VERSION 5.7 ;
  NOWIREEXTENSIONATPIN ON ;
  DIVIDERCHAR "/" ;
  BUSBITCHARS "[]" ;
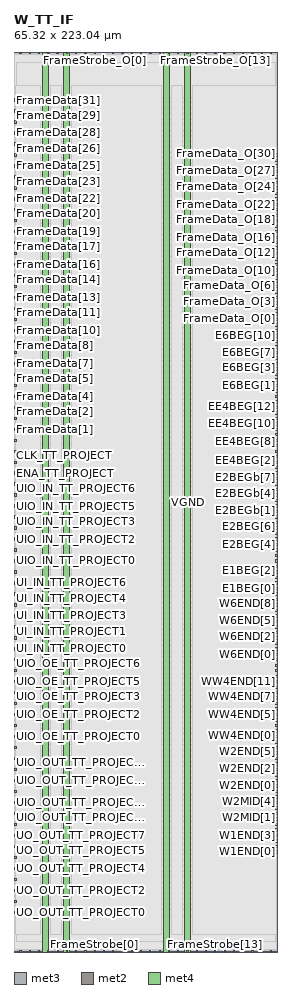
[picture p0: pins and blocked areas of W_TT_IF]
MACRO W_TT_IF
  CLASS BLOCK ;
  FOREIGN W_TT_IF ;
  ORIGIN 0.000 0.000 ;
  SIZE 65.320 BY 223.040 ;
  PIN CLK_TT_PROJECT
    DIRECTION OUTPUT ;
    USE SIGNAL ;
    ANTENNADIFFAREA 0.702900 ;
    PORT
      LAYER met3 ;
        RECT 0.000 121.080 0.600 121.680 ;
    END
  END CLK_TT_PROJECT
  PIN E1BEG[0]
    DIRECTION OUTPUT ;
    USE SIGNAL ;
    ANTENNADIFFAREA 0.702900 ;
    PORT
      LAYER met3 ;
        RECT 64.720 89.800 65.320 90.400 ;
    END
  END E1BEG[0]
  PIN E1BEG[1]
    DIRECTION OUTPUT ;
    USE SIGNAL ;
    ANTENNADIFFAREA 0.702900 ;
    PORT
      LAYER met3 ;
        RECT 64.720 91.160 65.320 91.760 ;
    END
  END E1BEG[1]
  PIN E1BEG[2]
    DIRECTION OUTPUT ;
    USE SIGNAL ;
    ANTENNADIFFAREA 0.702900 ;
    PORT
      LAYER met3 ;
        RECT 64.720 92.520 65.320 93.120 ;
    END
  END E1BEG[2]
  PIN E1BEG[3]
    DIRECTION OUTPUT ;
    USE SIGNAL ;
    ANTENNADIFFAREA 0.702900 ;
    PORT
      LAYER met3 ;
        RECT 64.720 93.880 65.320 94.480 ;
    END
  END E1BEG[3]
  PIN E2BEG[0]
    DIRECTION OUTPUT ;
    USE SIGNAL ;
    ANTENNADIFFAREA 0.702900 ;
    PORT
      LAYER met3 ;
        RECT 64.720 95.240 65.320 95.840 ;
    END
  END E2BEG[0]
  PIN E2BEG[1]
    DIRECTION OUTPUT ;
    USE SIGNAL ;
    ANTENNADIFFAREA 0.702900 ;
    PORT
      LAYER met3 ;
        RECT 64.720 96.600 65.320 97.200 ;
    END
  END E2BEG[1]
  PIN E2BEG[2]
    DIRECTION OUTPUT ;
    USE SIGNAL ;
    ANTENNADIFFAREA 0.702900 ;
    PORT
      LAYER met3 ;
        RECT 64.720 97.960 65.320 98.560 ;
    END
  END E2BEG[2]
  PIN E2BEG[3]
    DIRECTION OUTPUT ;
    USE SIGNAL ;
    ANTENNADIFFAREA 0.702900 ;
    PORT
      LAYER met3 ;
        RECT 64.720 99.320 65.320 99.920 ;
    END
  END E2BEG[3]
  PIN E2BEG[4]
    DIRECTION OUTPUT ;
    USE SIGNAL ;
    ANTENNADIFFAREA 0.702900 ;
    PORT
      LAYER met3 ;
        RECT 64.720 100.680 65.320 101.280 ;
    END
  END E2BEG[4]
  PIN E2BEG[5]
    DIRECTION OUTPUT ;
    USE SIGNAL ;
    ANTENNADIFFAREA 0.702900 ;
    PORT
      LAYER met3 ;
        RECT 64.720 102.040 65.320 102.640 ;
    END
  END E2BEG[5]
  PIN E2BEG[6]
    DIRECTION OUTPUT ;
    USE SIGNAL ;
    ANTENNADIFFAREA 0.702900 ;
    PORT
      LAYER met3 ;
        RECT 64.720 103.400 65.320 104.000 ;
    END
  END E2BEG[6]
  PIN E2BEG[7]
    DIRECTION OUTPUT ;
    USE SIGNAL ;
    ANTENNADIFFAREA 0.702900 ;
    PORT
      LAYER met3 ;
        RECT 64.720 104.760 65.320 105.360 ;
    END
  END E2BEG[7]
  PIN E2BEGb[0]
    DIRECTION OUTPUT ;
    USE SIGNAL ;
    ANTENNADIFFAREA 0.702900 ;
    PORT
      LAYER met3 ;
        RECT 64.720 106.120 65.320 106.720 ;
    END
  END E2BEGb[0]
  PIN E2BEGb[1]
    DIRECTION OUTPUT ;
    USE SIGNAL ;
    ANTENNADIFFAREA 0.702900 ;
    PORT
      LAYER met3 ;
        RECT 64.720 107.480 65.320 108.080 ;
    END
  END E2BEGb[1]
  PIN E2BEGb[2]
    DIRECTION OUTPUT ;
    USE SIGNAL ;
    ANTENNADIFFAREA 0.702900 ;
    PORT
      LAYER met3 ;
        RECT 64.720 108.840 65.320 109.440 ;
    END
  END E2BEGb[2]
  PIN E2BEGb[3]
    DIRECTION OUTPUT ;
    USE SIGNAL ;
    ANTENNADIFFAREA 0.702900 ;
    PORT
      LAYER met3 ;
        RECT 64.720 110.200 65.320 110.800 ;
    END
  END E2BEGb[3]
  PIN E2BEGb[4]
    DIRECTION OUTPUT ;
    USE SIGNAL ;
    ANTENNADIFFAREA 0.702900 ;
    PORT
      LAYER met3 ;
        RECT 64.720 111.560 65.320 112.160 ;
    END
  END E2BEGb[4]
  PIN E2BEGb[5]
    DIRECTION OUTPUT ;
    USE SIGNAL ;
    ANTENNADIFFAREA 0.702900 ;
    PORT
      LAYER met3 ;
        RECT 64.720 112.920 65.320 113.520 ;
    END
  END E2BEGb[5]
  PIN E2BEGb[6]
    DIRECTION OUTPUT ;
    USE SIGNAL ;
    ANTENNADIFFAREA 0.702900 ;
    PORT
      LAYER met3 ;
        RECT 64.720 114.280 65.320 114.880 ;
    END
  END E2BEGb[6]
  PIN E2BEGb[7]
    DIRECTION OUTPUT ;
    USE SIGNAL ;
    ANTENNADIFFAREA 0.702900 ;
    PORT
      LAYER met3 ;
        RECT 64.720 115.640 65.320 116.240 ;
    END
  END E2BEGb[7]
  PIN E6BEG[0]
    DIRECTION OUTPUT ;
    USE SIGNAL ;
    ANTENNADIFFAREA 0.702900 ;
    PORT
      LAYER met3 ;
        RECT 64.720 138.760 65.320 139.360 ;
    END
  END E6BEG[0]
  PIN E6BEG[10]
    DIRECTION OUTPUT ;
    USE SIGNAL ;
    ANTENNADIFFAREA 0.702900 ;
    PORT
      LAYER met3 ;
        RECT 64.720 152.360 65.320 152.960 ;
    END
  END E6BEG[10]
  PIN E6BEG[11]
    DIRECTION OUTPUT ;
    USE SIGNAL ;
    ANTENNADIFFAREA 0.702900 ;
    PORT
      LAYER met3 ;
        RECT 64.720 153.720 65.320 154.320 ;
    END
  END E6BEG[11]
  PIN E6BEG[1]
    DIRECTION OUTPUT ;
    USE SIGNAL ;
    ANTENNADIFFAREA 0.702900 ;
    PORT
      LAYER met3 ;
        RECT 64.720 140.120 65.320 140.720 ;
    END
  END E6BEG[1]
  PIN E6BEG[2]
    DIRECTION OUTPUT ;
    USE SIGNAL ;
    ANTENNADIFFAREA 0.702900 ;
    PORT
      LAYER met3 ;
        RECT 64.720 141.480 65.320 142.080 ;
    END
  END E6BEG[2]
  PIN E6BEG[3]
    DIRECTION OUTPUT ;
    USE SIGNAL ;
    ANTENNADIFFAREA 0.702900 ;
    PORT
      LAYER met3 ;
        RECT 64.720 142.840 65.320 143.440 ;
    END
  END E6BEG[3]
  PIN E6BEG[4]
    DIRECTION OUTPUT ;
    USE SIGNAL ;
    ANTENNADIFFAREA 0.702900 ;
    PORT
      LAYER met3 ;
        RECT 64.720 144.200 65.320 144.800 ;
    END
  END E6BEG[4]
  PIN E6BEG[5]
    DIRECTION OUTPUT ;
    USE SIGNAL ;
    ANTENNADIFFAREA 0.702900 ;
    PORT
      LAYER met3 ;
        RECT 64.720 145.560 65.320 146.160 ;
    END
  END E6BEG[5]
  PIN E6BEG[6]
    DIRECTION OUTPUT ;
    USE SIGNAL ;
    ANTENNADIFFAREA 0.702900 ;
    PORT
      LAYER met3 ;
        RECT 64.720 146.920 65.320 147.520 ;
    END
  END E6BEG[6]
  PIN E6BEG[7]
    DIRECTION OUTPUT ;
    USE SIGNAL ;
    ANTENNADIFFAREA 0.702900 ;
    PORT
      LAYER met3 ;
        RECT 64.720 148.280 65.320 148.880 ;
    END
  END E6BEG[7]
  PIN E6BEG[8]
    DIRECTION OUTPUT ;
    USE SIGNAL ;
    ANTENNADIFFAREA 0.702900 ;
    PORT
      LAYER met3 ;
        RECT 64.720 149.640 65.320 150.240 ;
    END
  END E6BEG[8]
  PIN E6BEG[9]
    DIRECTION OUTPUT ;
    USE SIGNAL ;
    ANTENNADIFFAREA 0.702900 ;
    PORT
      LAYER met3 ;
        RECT 64.720 151.000 65.320 151.600 ;
    END
  END E6BEG[9]
  PIN EE4BEG[0]
    DIRECTION OUTPUT ;
    USE SIGNAL ;
    ANTENNADIFFAREA 0.702900 ;
    PORT
      LAYER met3 ;
        RECT 64.720 117.000 65.320 117.600 ;
    END
  END EE4BEG[0]
  PIN EE4BEG[10]
    DIRECTION OUTPUT ;
    USE SIGNAL ;
    ANTENNADIFFAREA 0.702900 ;
    PORT
      LAYER met3 ;
        RECT 64.720 130.600 65.320 131.200 ;
    END
  END EE4BEG[10]
  PIN EE4BEG[11]
    DIRECTION OUTPUT ;
    USE SIGNAL ;
    ANTENNADIFFAREA 0.702900 ;
    PORT
      LAYER met3 ;
        RECT 64.720 131.960 65.320 132.560 ;
    END
  END EE4BEG[11]
  PIN EE4BEG[12]
    DIRECTION OUTPUT ;
    USE SIGNAL ;
    ANTENNADIFFAREA 0.702900 ;
    PORT
      LAYER met3 ;
        RECT 64.720 133.320 65.320 133.920 ;
    END
  END EE4BEG[12]
  PIN EE4BEG[13]
    DIRECTION OUTPUT ;
    USE SIGNAL ;
    ANTENNADIFFAREA 0.702900 ;
    PORT
      LAYER met3 ;
        RECT 64.720 134.680 65.320 135.280 ;
    END
  END EE4BEG[13]
  PIN EE4BEG[14]
    DIRECTION OUTPUT ;
    USE SIGNAL ;
    ANTENNADIFFAREA 0.702900 ;
    PORT
      LAYER met3 ;
        RECT 64.720 136.040 65.320 136.640 ;
    END
  END EE4BEG[14]
  PIN EE4BEG[15]
    DIRECTION OUTPUT ;
    USE SIGNAL ;
    ANTENNADIFFAREA 0.702900 ;
    PORT
      LAYER met3 ;
        RECT 64.720 137.400 65.320 138.000 ;
    END
  END EE4BEG[15]
  PIN EE4BEG[1]
    DIRECTION OUTPUT ;
    USE SIGNAL ;
    ANTENNADIFFAREA 0.702900 ;
    PORT
      LAYER met3 ;
        RECT 64.720 118.360 65.320 118.960 ;
    END
  END EE4BEG[1]
  PIN EE4BEG[2]
    DIRECTION OUTPUT ;
    USE SIGNAL ;
    ANTENNADIFFAREA 0.702900 ;
    PORT
      LAYER met3 ;
        RECT 64.720 119.720 65.320 120.320 ;
    END
  END EE4BEG[2]
  PIN EE4BEG[3]
    DIRECTION OUTPUT ;
    USE SIGNAL ;
    ANTENNADIFFAREA 0.702900 ;
    PORT
      LAYER met3 ;
        RECT 64.720 121.080 65.320 121.680 ;
    END
  END EE4BEG[3]
  PIN EE4BEG[4]
    DIRECTION OUTPUT ;
    USE SIGNAL ;
    ANTENNADIFFAREA 0.702900 ;
    PORT
      LAYER met3 ;
        RECT 64.720 122.440 65.320 123.040 ;
    END
  END EE4BEG[4]
  PIN EE4BEG[5]
    DIRECTION OUTPUT ;
    USE SIGNAL ;
    ANTENNADIFFAREA 0.702900 ;
    PORT
      LAYER met3 ;
        RECT 64.720 123.800 65.320 124.400 ;
    END
  END EE4BEG[5]
  PIN EE4BEG[6]
    DIRECTION OUTPUT ;
    USE SIGNAL ;
    ANTENNADIFFAREA 0.702900 ;
    PORT
      LAYER met3 ;
        RECT 64.720 125.160 65.320 125.760 ;
    END
  END EE4BEG[6]
  PIN EE4BEG[7]
    DIRECTION OUTPUT ;
    USE SIGNAL ;
    ANTENNADIFFAREA 0.702900 ;
    PORT
      LAYER met3 ;
        RECT 64.720 126.520 65.320 127.120 ;
    END
  END EE4BEG[7]
  PIN EE4BEG[8]
    DIRECTION OUTPUT ;
    USE SIGNAL ;
    ANTENNADIFFAREA 0.702900 ;
    PORT
      LAYER met3 ;
        RECT 64.720 127.880 65.320 128.480 ;
    END
  END EE4BEG[8]
  PIN EE4BEG[9]
    DIRECTION OUTPUT ;
    USE SIGNAL ;
    ANTENNADIFFAREA 0.702900 ;
    PORT
      LAYER met3 ;
        RECT 64.720 129.240 65.320 129.840 ;
    END
  END EE4BEG[9]
  PIN ENA_TT_PROJECT
    DIRECTION OUTPUT ;
    USE SIGNAL ;
    ANTENNADIFFAREA 0.702900 ;
    PORT
      LAYER met3 ;
        RECT 0.000 118.360 0.600 118.960 ;
    END
  END ENA_TT_PROJECT
  PIN FrameData[0]
    DIRECTION INPUT ;
    USE SIGNAL ;
    ANTENNAGATEAREA 0.954000 ;
    PORT
      LAYER met3 ;
        RECT 0.000 126.520 0.600 127.120 ;
    END
  END FrameData[0]
  PIN FrameData[10]
    DIRECTION INPUT ;
    USE SIGNAL ;
    ANTENNAGATEAREA 1.823400 ;
    ANTENNADIFFAREA 0.869400 ;
    PORT
      LAYER met3 ;
        RECT 0.000 153.720 0.600 154.320 ;
    END
  END FrameData[10]
  PIN FrameData[11]
    DIRECTION INPUT ;
    USE SIGNAL ;
    ANTENNAGATEAREA 0.954000 ;
    PORT
      LAYER met3 ;
        RECT 0.000 156.440 0.600 157.040 ;
    END
  END FrameData[11]
  PIN FrameData[12]
    DIRECTION INPUT ;
    USE SIGNAL ;
    ANTENNAGATEAREA 0.954000 ;
    PORT
      LAYER met3 ;
        RECT 0.000 159.160 0.600 159.760 ;
    END
  END FrameData[12]
  PIN FrameData[13]
    DIRECTION INPUT ;
    USE SIGNAL ;
    ANTENNAGATEAREA 1.823400 ;
    ANTENNADIFFAREA 0.869400 ;
    PORT
      LAYER met3 ;
        RECT 0.000 161.880 0.600 162.480 ;
    END
  END FrameData[13]
  PIN FrameData[14]
    DIRECTION INPUT ;
    USE SIGNAL ;
    ANTENNAGATEAREA 0.954000 ;
    PORT
      LAYER met3 ;
        RECT 0.000 164.600 0.600 165.200 ;
    END
  END FrameData[14]
  PIN FrameData[15]
    DIRECTION INPUT ;
    USE SIGNAL ;
    ANTENNAGATEAREA 0.954000 ;
    PORT
      LAYER met3 ;
        RECT 0.000 167.320 0.600 167.920 ;
    END
  END FrameData[15]
  PIN FrameData[16]
    DIRECTION INPUT ;
    USE SIGNAL ;
    ANTENNAGATEAREA 0.954000 ;
    PORT
      LAYER met3 ;
        RECT 0.000 170.040 0.600 170.640 ;
    END
  END FrameData[16]
  PIN FrameData[17]
    DIRECTION INPUT ;
    USE SIGNAL ;
    ANTENNAGATEAREA 0.954000 ;
    PORT
      LAYER met3 ;
        RECT 0.000 172.760 0.600 173.360 ;
    END
  END FrameData[17]
  PIN FrameData[18]
    DIRECTION INPUT ;
    USE SIGNAL ;
    ANTENNAGATEAREA 0.954000 ;
    PORT
      LAYER met3 ;
        RECT 0.000 175.480 0.600 176.080 ;
    END
  END FrameData[18]
  PIN FrameData[19]
    DIRECTION INPUT ;
    USE SIGNAL ;
    ANTENNAGATEAREA 0.954000 ;
    PORT
      LAYER met3 ;
        RECT 0.000 178.200 0.600 178.800 ;
    END
  END FrameData[19]
  PIN FrameData[1]
    DIRECTION INPUT ;
    USE SIGNAL ;
    ANTENNAGATEAREA 0.954000 ;
    PORT
      LAYER met3 ;
        RECT 0.000 129.240 0.600 129.840 ;
    END
  END FrameData[1]
  PIN FrameData[20]
    DIRECTION INPUT ;
    USE SIGNAL ;
    ANTENNAGATEAREA 1.388700 ;
    ANTENNADIFFAREA 0.434700 ;
    PORT
      LAYER met3 ;
        RECT 0.000 180.920 0.600 181.520 ;
    END
  END FrameData[20]
  PIN FrameData[21]
    DIRECTION INPUT ;
    USE SIGNAL ;
    ANTENNAGATEAREA 0.954000 ;
    PORT
      LAYER met3 ;
        RECT 0.000 183.640 0.600 184.240 ;
    END
  END FrameData[21]
  PIN FrameData[22]
    DIRECTION INPUT ;
    USE SIGNAL ;
    ANTENNAGATEAREA 1.388700 ;
    ANTENNADIFFAREA 0.434700 ;
    PORT
      LAYER met3 ;
        RECT 0.000 186.360 0.600 186.960 ;
    END
  END FrameData[22]
  PIN FrameData[23]
    DIRECTION INPUT ;
    USE SIGNAL ;
    ANTENNAGATEAREA 0.954000 ;
    PORT
      LAYER met3 ;
        RECT 0.000 189.080 0.600 189.680 ;
    END
  END FrameData[23]
  PIN FrameData[24]
    DIRECTION INPUT ;
    USE SIGNAL ;
    ANTENNAGATEAREA 0.954000 ;
    PORT
      LAYER met3 ;
        RECT 0.000 191.800 0.600 192.400 ;
    END
  END FrameData[24]
  PIN FrameData[25]
    DIRECTION INPUT ;
    USE SIGNAL ;
    ANTENNAGATEAREA 0.954000 ;
    PORT
      LAYER met3 ;
        RECT 0.000 194.520 0.600 195.120 ;
    END
  END FrameData[25]
  PIN FrameData[26]
    DIRECTION INPUT ;
    USE SIGNAL ;
    ANTENNAGATEAREA 0.954000 ;
    PORT
      LAYER met3 ;
        RECT 0.000 197.240 0.600 197.840 ;
    END
  END FrameData[26]
  PIN FrameData[27]
    DIRECTION INPUT ;
    USE SIGNAL ;
    ANTENNAGATEAREA 1.113000 ;
    PORT
      LAYER met3 ;
        RECT 0.000 199.960 0.600 200.560 ;
    END
  END FrameData[27]
  PIN FrameData[28]
    DIRECTION INPUT ;
    USE SIGNAL ;
    ANTENNAGATEAREA 1.113000 ;
    PORT
      LAYER met3 ;
        RECT 0.000 202.680 0.600 203.280 ;
    END
  END FrameData[28]
  PIN FrameData[29]
    DIRECTION INPUT ;
    USE SIGNAL ;
    ANTENNAGATEAREA 1.113000 ;
    PORT
      LAYER met3 ;
        RECT 0.000 205.400 0.600 206.000 ;
    END
  END FrameData[29]
  PIN FrameData[2]
    DIRECTION INPUT ;
    USE SIGNAL ;
    ANTENNAGATEAREA 0.954000 ;
    PORT
      LAYER met3 ;
        RECT 0.000 131.960 0.600 132.560 ;
    END
  END FrameData[2]
  PIN FrameData[30]
    DIRECTION INPUT ;
    USE SIGNAL ;
    ANTENNAGATEAREA 1.113000 ;
    PORT
      LAYER met3 ;
        RECT 0.000 208.120 0.600 208.720 ;
    END
  END FrameData[30]
  PIN FrameData[31]
    DIRECTION INPUT ;
    USE SIGNAL ;
    ANTENNAGATEAREA 1.113000 ;
    PORT
      LAYER met3 ;
        RECT 0.000 210.840 0.600 211.440 ;
    END
  END FrameData[31]
  PIN FrameData[3]
    DIRECTION INPUT ;
    USE SIGNAL ;
    ANTENNAGATEAREA 1.388700 ;
    ANTENNADIFFAREA 0.434700 ;
    PORT
      LAYER met3 ;
        RECT 0.000 134.680 0.600 135.280 ;
    END
  END FrameData[3]
  PIN FrameData[4]
    DIRECTION INPUT ;
    USE SIGNAL ;
    ANTENNAGATEAREA 1.388700 ;
    ANTENNADIFFAREA 0.434700 ;
    PORT
      LAYER met3 ;
        RECT 0.000 137.400 0.600 138.000 ;
    END
  END FrameData[4]
  PIN FrameData[5]
    DIRECTION INPUT ;
    USE SIGNAL ;
    ANTENNAGATEAREA 0.954000 ;
    PORT
      LAYER met3 ;
        RECT 0.000 140.120 0.600 140.720 ;
    END
  END FrameData[5]
  PIN FrameData[6]
    DIRECTION INPUT ;
    USE SIGNAL ;
    ANTENNAGATEAREA 0.954000 ;
    PORT
      LAYER met3 ;
        RECT 0.000 142.840 0.600 143.440 ;
    END
  END FrameData[6]
  PIN FrameData[7]
    DIRECTION INPUT ;
    USE SIGNAL ;
    ANTENNAGATEAREA 0.954000 ;
    PORT
      LAYER met3 ;
        RECT 0.000 145.560 0.600 146.160 ;
    END
  END FrameData[7]
  PIN FrameData[8]
    DIRECTION INPUT ;
    USE SIGNAL ;
    ANTENNAGATEAREA 1.388700 ;
    ANTENNADIFFAREA 0.434700 ;
    PORT
      LAYER met3 ;
        RECT 0.000 148.280 0.600 148.880 ;
    END
  END FrameData[8]
  PIN FrameData[9]
    DIRECTION INPUT ;
    USE SIGNAL ;
    ANTENNAGATEAREA 0.954000 ;
    PORT
      LAYER met3 ;
        RECT 0.000 151.000 0.600 151.600 ;
    END
  END FrameData[9]
  PIN FrameData_O[0]
    DIRECTION OUTPUT ;
    USE SIGNAL ;
    ANTENNADIFFAREA 0.702900 ;
    PORT
      LAYER met3 ;
        RECT 64.720 155.080 65.320 155.680 ;
    END
  END FrameData_O[0]
  PIN FrameData_O[10]
    DIRECTION OUTPUT ;
    USE SIGNAL ;
    ANTENNADIFFAREA 0.702900 ;
    PORT
      LAYER met3 ;
        RECT 64.720 168.680 65.320 169.280 ;
    END
  END FrameData_O[10]
  PIN FrameData_O[11]
    DIRECTION OUTPUT ;
    USE SIGNAL ;
    ANTENNADIFFAREA 0.702900 ;
    PORT
      LAYER met3 ;
        RECT 64.720 170.040 65.320 170.640 ;
    END
  END FrameData_O[11]
  PIN FrameData_O[12]
    DIRECTION OUTPUT ;
    USE SIGNAL ;
    ANTENNADIFFAREA 0.702900 ;
    PORT
      LAYER met3 ;
        RECT 64.720 171.400 65.320 172.000 ;
    END
  END FrameData_O[12]
  PIN FrameData_O[13]
    DIRECTION OUTPUT ;
    USE SIGNAL ;
    ANTENNADIFFAREA 0.702900 ;
    PORT
      LAYER met3 ;
        RECT 64.720 172.760 65.320 173.360 ;
    END
  END FrameData_O[13]
  PIN FrameData_O[14]
    DIRECTION OUTPUT ;
    USE SIGNAL ;
    ANTENNADIFFAREA 0.702900 ;
    PORT
      LAYER met3 ;
        RECT 64.720 174.120 65.320 174.720 ;
    END
  END FrameData_O[14]
  PIN FrameData_O[15]
    DIRECTION OUTPUT ;
    USE SIGNAL ;
    ANTENNADIFFAREA 0.702900 ;
    PORT
      LAYER met3 ;
        RECT 64.720 175.480 65.320 176.080 ;
    END
  END FrameData_O[15]
  PIN FrameData_O[16]
    DIRECTION OUTPUT ;
    USE SIGNAL ;
    ANTENNADIFFAREA 0.702900 ;
    PORT
      LAYER met3 ;
        RECT 64.720 176.840 65.320 177.440 ;
    END
  END FrameData_O[16]
  PIN FrameData_O[17]
    DIRECTION OUTPUT ;
    USE SIGNAL ;
    ANTENNADIFFAREA 0.702900 ;
    PORT
      LAYER met3 ;
        RECT 64.720 178.200 65.320 178.800 ;
    END
  END FrameData_O[17]
  PIN FrameData_O[18]
    DIRECTION OUTPUT ;
    USE SIGNAL ;
    ANTENNADIFFAREA 0.702900 ;
    PORT
      LAYER met3 ;
        RECT 64.720 179.560 65.320 180.160 ;
    END
  END FrameData_O[18]
  PIN FrameData_O[19]
    DIRECTION OUTPUT ;
    USE SIGNAL ;
    ANTENNADIFFAREA 0.702900 ;
    PORT
      LAYER met3 ;
        RECT 64.720 180.920 65.320 181.520 ;
    END
  END FrameData_O[19]
  PIN FrameData_O[1]
    DIRECTION OUTPUT ;
    USE SIGNAL ;
    ANTENNADIFFAREA 0.702900 ;
    PORT
      LAYER met3 ;
        RECT 64.720 156.440 65.320 157.040 ;
    END
  END FrameData_O[1]
  PIN FrameData_O[20]
    DIRECTION OUTPUT ;
    USE SIGNAL ;
    ANTENNADIFFAREA 0.702900 ;
    PORT
      LAYER met3 ;
        RECT 64.720 182.280 65.320 182.880 ;
    END
  END FrameData_O[20]
  PIN FrameData_O[21]
    DIRECTION OUTPUT ;
    USE SIGNAL ;
    ANTENNADIFFAREA 0.702900 ;
    PORT
      LAYER met3 ;
        RECT 64.720 183.640 65.320 184.240 ;
    END
  END FrameData_O[21]
  PIN FrameData_O[22]
    DIRECTION OUTPUT ;
    USE SIGNAL ;
    ANTENNADIFFAREA 0.702900 ;
    PORT
      LAYER met3 ;
        RECT 64.720 185.000 65.320 185.600 ;
    END
  END FrameData_O[22]
  PIN FrameData_O[23]
    DIRECTION OUTPUT ;
    USE SIGNAL ;
    ANTENNADIFFAREA 0.702900 ;
    PORT
      LAYER met3 ;
        RECT 64.720 186.360 65.320 186.960 ;
    END
  END FrameData_O[23]
  PIN FrameData_O[24]
    DIRECTION OUTPUT ;
    USE SIGNAL ;
    ANTENNADIFFAREA 0.702900 ;
    PORT
      LAYER met3 ;
        RECT 64.720 187.720 65.320 188.320 ;
    END
  END FrameData_O[24]
  PIN FrameData_O[25]
    DIRECTION OUTPUT ;
    USE SIGNAL ;
    ANTENNADIFFAREA 0.702900 ;
    PORT
      LAYER met3 ;
        RECT 64.720 189.080 65.320 189.680 ;
    END
  END FrameData_O[25]
  PIN FrameData_O[26]
    DIRECTION OUTPUT ;
    USE SIGNAL ;
    ANTENNADIFFAREA 0.702900 ;
    PORT
      LAYER met3 ;
        RECT 64.720 190.440 65.320 191.040 ;
    END
  END FrameData_O[26]
  PIN FrameData_O[27]
    DIRECTION OUTPUT ;
    USE SIGNAL ;
    ANTENNADIFFAREA 0.702900 ;
    PORT
      LAYER met3 ;
        RECT 64.720 191.800 65.320 192.400 ;
    END
  END FrameData_O[27]
  PIN FrameData_O[28]
    DIRECTION OUTPUT ;
    USE SIGNAL ;
    ANTENNADIFFAREA 0.702900 ;
    PORT
      LAYER met3 ;
        RECT 64.720 193.160 65.320 193.760 ;
    END
  END FrameData_O[28]
  PIN FrameData_O[29]
    DIRECTION OUTPUT ;
    USE SIGNAL ;
    ANTENNADIFFAREA 0.702900 ;
    PORT
      LAYER met3 ;
        RECT 64.720 194.520 65.320 195.120 ;
    END
  END FrameData_O[29]
  PIN FrameData_O[2]
    DIRECTION OUTPUT ;
    USE SIGNAL ;
    ANTENNADIFFAREA 0.702900 ;
    PORT
      LAYER met3 ;
        RECT 64.720 157.800 65.320 158.400 ;
    END
  END FrameData_O[2]
  PIN FrameData_O[30]
    DIRECTION OUTPUT ;
    USE SIGNAL ;
    ANTENNADIFFAREA 0.702900 ;
    PORT
      LAYER met3 ;
        RECT 64.720 195.880 65.320 196.480 ;
    END
  END FrameData_O[30]
  PIN FrameData_O[31]
    DIRECTION OUTPUT ;
    USE SIGNAL ;
    ANTENNADIFFAREA 0.702900 ;
    PORT
      LAYER met3 ;
        RECT 64.720 197.240 65.320 197.840 ;
    END
  END FrameData_O[31]
  PIN FrameData_O[3]
    DIRECTION OUTPUT ;
    USE SIGNAL ;
    ANTENNADIFFAREA 0.702900 ;
    PORT
      LAYER met3 ;
        RECT 64.720 159.160 65.320 159.760 ;
    END
  END FrameData_O[3]
  PIN FrameData_O[4]
    DIRECTION OUTPUT ;
    USE SIGNAL ;
    ANTENNADIFFAREA 0.702900 ;
    PORT
      LAYER met3 ;
        RECT 64.720 160.520 65.320 161.120 ;
    END
  END FrameData_O[4]
  PIN FrameData_O[5]
    DIRECTION OUTPUT ;
    USE SIGNAL ;
    ANTENNADIFFAREA 0.702900 ;
    PORT
      LAYER met3 ;
        RECT 64.720 161.880 65.320 162.480 ;
    END
  END FrameData_O[5]
  PIN FrameData_O[6]
    DIRECTION OUTPUT ;
    USE SIGNAL ;
    ANTENNADIFFAREA 0.702900 ;
    PORT
      LAYER met3 ;
        RECT 64.720 163.240 65.320 163.840 ;
    END
  END FrameData_O[6]
  PIN FrameData_O[7]
    DIRECTION OUTPUT ;
    USE SIGNAL ;
    ANTENNADIFFAREA 0.702900 ;
    PORT
      LAYER met3 ;
        RECT 64.720 164.600 65.320 165.200 ;
    END
  END FrameData_O[7]
  PIN FrameData_O[8]
    DIRECTION OUTPUT ;
    USE SIGNAL ;
    ANTENNADIFFAREA 0.702900 ;
    PORT
      LAYER met3 ;
        RECT 64.720 165.960 65.320 166.560 ;
    END
  END FrameData_O[8]
  PIN FrameData_O[9]
    DIRECTION OUTPUT ;
    USE SIGNAL ;
    ANTENNADIFFAREA 0.702900 ;
    PORT
      LAYER met3 ;
        RECT 64.720 167.320 65.320 167.920 ;
    END
  END FrameData_O[9]
  PIN FrameStrobe[0]
    DIRECTION INPUT ;
    USE SIGNAL ;
    ANTENNAGATEAREA 5.247000 ;
    PORT
      LAYER met2 ;
        RECT 19.870 0.000 20.150 0.280 ;
    END
  END FrameStrobe[0]
  PIN FrameStrobe[10]
    DIRECTION INPUT ;
    USE SIGNAL ;
    ANTENNAGATEAREA 0.159000 ;
    PORT
      LAYER met2 ;
        RECT 42.870 0.000 43.150 0.280 ;
    END
  END FrameStrobe[10]
  PIN FrameStrobe[11]
    DIRECTION INPUT ;
    USE SIGNAL ;
    ANTENNAGATEAREA 0.159000 ;
    PORT
      LAYER met2 ;
        RECT 45.170 0.000 45.450 0.280 ;
    END
  END FrameStrobe[11]
  PIN FrameStrobe[12]
    DIRECTION INPUT ;
    USE SIGNAL ;
    ANTENNAGATEAREA 0.159000 ;
    PORT
      LAYER met2 ;
        RECT 47.470 0.000 47.750 0.280 ;
    END
  END FrameStrobe[12]
  PIN FrameStrobe[13]
    DIRECTION INPUT ;
    USE SIGNAL ;
    ANTENNAGATEAREA 0.159000 ;
    PORT
      LAYER met2 ;
        RECT 49.770 0.000 50.050 0.280 ;
    END
  END FrameStrobe[13]
  PIN FrameStrobe[14]
    DIRECTION INPUT ;
    USE SIGNAL ;
    ANTENNAGATEAREA 0.159000 ;
    PORT
      LAYER met2 ;
        RECT 52.070 0.000 52.350 0.280 ;
    END
  END FrameStrobe[14]
  PIN FrameStrobe[15]
    DIRECTION INPUT ;
    USE SIGNAL ;
    ANTENNAGATEAREA 0.159000 ;
    PORT
      LAYER met2 ;
        RECT 54.370 0.000 54.650 0.280 ;
    END
  END FrameStrobe[15]
  PIN FrameStrobe[16]
    DIRECTION INPUT ;
    USE SIGNAL ;
    ANTENNAGATEAREA 0.159000 ;
    PORT
      LAYER met2 ;
        RECT 56.670 0.000 56.950 0.280 ;
    END
  END FrameStrobe[16]
  PIN FrameStrobe[17]
    DIRECTION INPUT ;
    USE SIGNAL ;
    ANTENNAGATEAREA 0.159000 ;
    PORT
      LAYER met2 ;
        RECT 58.970 0.000 59.250 0.280 ;
    END
  END FrameStrobe[17]
  PIN FrameStrobe[18]
    DIRECTION INPUT ;
    USE SIGNAL ;
    ANTENNAGATEAREA 0.159000 ;
    PORT
      LAYER met2 ;
        RECT 61.270 0.000 61.550 0.280 ;
    END
  END FrameStrobe[18]
  PIN FrameStrobe[19]
    DIRECTION INPUT ;
    USE SIGNAL ;
    ANTENNAGATEAREA 0.159000 ;
    PORT
      LAYER met2 ;
        RECT 63.570 0.000 63.850 0.280 ;
    END
  END FrameStrobe[19]
  PIN FrameStrobe[1]
    DIRECTION INPUT ;
    USE SIGNAL ;
    ANTENNAGATEAREA 5.247000 ;
    PORT
      LAYER met2 ;
        RECT 22.170 0.000 22.450 0.280 ;
    END
  END FrameStrobe[1]
  PIN FrameStrobe[2]
    DIRECTION INPUT ;
    USE SIGNAL ;
    ANTENNAGATEAREA 5.247000 ;
    PORT
      LAYER met2 ;
        RECT 24.470 0.000 24.750 0.280 ;
    END
  END FrameStrobe[2]
  PIN FrameStrobe[3]
    DIRECTION INPUT ;
    USE SIGNAL ;
    ANTENNAGATEAREA 5.247000 ;
    PORT
      LAYER met2 ;
        RECT 26.770 0.000 27.050 0.280 ;
    END
  END FrameStrobe[3]
  PIN FrameStrobe[4]
    DIRECTION INPUT ;
    USE SIGNAL ;
    ANTENNAGATEAREA 5.247000 ;
    PORT
      LAYER met2 ;
        RECT 29.070 0.000 29.350 0.280 ;
    END
  END FrameStrobe[4]
  PIN FrameStrobe[5]
    DIRECTION INPUT ;
    USE SIGNAL ;
    ANTENNAGATEAREA 0.954000 ;
    PORT
      LAYER met2 ;
        RECT 31.370 0.000 31.650 0.280 ;
    END
  END FrameStrobe[5]
  PIN FrameStrobe[6]
    DIRECTION INPUT ;
    USE SIGNAL ;
    ANTENNAGATEAREA 0.159000 ;
    PORT
      LAYER met2 ;
        RECT 33.670 0.000 33.950 0.280 ;
    END
  END FrameStrobe[6]
  PIN FrameStrobe[7]
    DIRECTION INPUT ;
    USE SIGNAL ;
    ANTENNAGATEAREA 0.159000 ;
    PORT
      LAYER met2 ;
        RECT 35.970 0.000 36.250 0.280 ;
    END
  END FrameStrobe[7]
  PIN FrameStrobe[8]
    DIRECTION INPUT ;
    USE SIGNAL ;
    ANTENNAGATEAREA 0.159000 ;
    PORT
      LAYER met2 ;
        RECT 38.270 0.000 38.550 0.280 ;
    END
  END FrameStrobe[8]
  PIN FrameStrobe[9]
    DIRECTION INPUT ;
    USE SIGNAL ;
    ANTENNAGATEAREA 0.159000 ;
    PORT
      LAYER met2 ;
        RECT 40.570 0.000 40.850 0.280 ;
    END
  END FrameStrobe[9]
  PIN FrameStrobe_O[0]
    DIRECTION OUTPUT ;
    USE SIGNAL ;
    ANTENNADIFFAREA 0.702900 ;
    PORT
      LAYER met2 ;
        RECT 19.870 222.760 20.150 223.040 ;
    END
  END FrameStrobe_O[0]
  PIN FrameStrobe_O[10]
    DIRECTION OUTPUT ;
    USE SIGNAL ;
    ANTENNADIFFAREA 0.702900 ;
    PORT
      LAYER met2 ;
        RECT 42.870 222.760 43.150 223.040 ;
    END
  END FrameStrobe_O[10]
  PIN FrameStrobe_O[11]
    DIRECTION OUTPUT ;
    USE SIGNAL ;
    ANTENNADIFFAREA 0.702900 ;
    PORT
      LAYER met2 ;
        RECT 45.170 222.760 45.450 223.040 ;
    END
  END FrameStrobe_O[11]
  PIN FrameStrobe_O[12]
    DIRECTION OUTPUT ;
    USE SIGNAL ;
    ANTENNADIFFAREA 0.702900 ;
    PORT
      LAYER met2 ;
        RECT 47.470 222.760 47.750 223.040 ;
    END
  END FrameStrobe_O[12]
  PIN FrameStrobe_O[13]
    DIRECTION OUTPUT ;
    USE SIGNAL ;
    ANTENNADIFFAREA 0.702900 ;
    PORT
      LAYER met2 ;
        RECT 49.770 222.760 50.050 223.040 ;
    END
  END FrameStrobe_O[13]
  PIN FrameStrobe_O[14]
    DIRECTION OUTPUT ;
    USE SIGNAL ;
    ANTENNADIFFAREA 0.702900 ;
    PORT
      LAYER met2 ;
        RECT 52.070 222.760 52.350 223.040 ;
    END
  END FrameStrobe_O[14]
  PIN FrameStrobe_O[15]
    DIRECTION OUTPUT ;
    USE SIGNAL ;
    ANTENNADIFFAREA 0.702900 ;
    PORT
      LAYER met2 ;
        RECT 54.370 222.760 54.650 223.040 ;
    END
  END FrameStrobe_O[15]
  PIN FrameStrobe_O[16]
    DIRECTION OUTPUT ;
    USE SIGNAL ;
    ANTENNADIFFAREA 0.702900 ;
    PORT
      LAYER met2 ;
        RECT 56.670 222.760 56.950 223.040 ;
    END
  END FrameStrobe_O[16]
  PIN FrameStrobe_O[17]
    DIRECTION OUTPUT ;
    USE SIGNAL ;
    ANTENNADIFFAREA 0.702900 ;
    PORT
      LAYER met2 ;
        RECT 58.970 222.760 59.250 223.040 ;
    END
  END FrameStrobe_O[17]
  PIN FrameStrobe_O[18]
    DIRECTION OUTPUT ;
    USE SIGNAL ;
    ANTENNADIFFAREA 0.702900 ;
    PORT
      LAYER met2 ;
        RECT 61.270 222.760 61.550 223.040 ;
    END
  END FrameStrobe_O[18]
  PIN FrameStrobe_O[19]
    DIRECTION OUTPUT ;
    USE SIGNAL ;
    ANTENNADIFFAREA 0.702900 ;
    PORT
      LAYER met2 ;
        RECT 63.570 222.760 63.850 223.040 ;
    END
  END FrameStrobe_O[19]
  PIN FrameStrobe_O[1]
    DIRECTION OUTPUT ;
    USE SIGNAL ;
    ANTENNADIFFAREA 0.702900 ;
    PORT
      LAYER met2 ;
        RECT 22.170 222.760 22.450 223.040 ;
    END
  END FrameStrobe_O[1]
  PIN FrameStrobe_O[2]
    DIRECTION OUTPUT ;
    USE SIGNAL ;
    ANTENNADIFFAREA 0.702900 ;
    PORT
      LAYER met2 ;
        RECT 24.470 222.760 24.750 223.040 ;
    END
  END FrameStrobe_O[2]
  PIN FrameStrobe_O[3]
    DIRECTION OUTPUT ;
    USE SIGNAL ;
    ANTENNADIFFAREA 0.702900 ;
    PORT
      LAYER met2 ;
        RECT 26.770 222.760 27.050 223.040 ;
    END
  END FrameStrobe_O[3]
  PIN FrameStrobe_O[4]
    DIRECTION OUTPUT ;
    USE SIGNAL ;
    ANTENNADIFFAREA 0.702900 ;
    PORT
      LAYER met2 ;
        RECT 29.070 222.760 29.350 223.040 ;
    END
  END FrameStrobe_O[4]
  PIN FrameStrobe_O[5]
    DIRECTION OUTPUT ;
    USE SIGNAL ;
    ANTENNADIFFAREA 0.702900 ;
    PORT
      LAYER met2 ;
        RECT 31.370 222.760 31.650 223.040 ;
    END
  END FrameStrobe_O[5]
  PIN FrameStrobe_O[6]
    DIRECTION OUTPUT ;
    USE SIGNAL ;
    ANTENNADIFFAREA 0.702900 ;
    PORT
      LAYER met2 ;
        RECT 33.670 222.760 33.950 223.040 ;
    END
  END FrameStrobe_O[6]
  PIN FrameStrobe_O[7]
    DIRECTION OUTPUT ;
    USE SIGNAL ;
    ANTENNADIFFAREA 0.702900 ;
    PORT
      LAYER met2 ;
        RECT 35.970 222.760 36.250 223.040 ;
    END
  END FrameStrobe_O[7]
  PIN FrameStrobe_O[8]
    DIRECTION OUTPUT ;
    USE SIGNAL ;
    ANTENNADIFFAREA 0.702900 ;
    PORT
      LAYER met2 ;
        RECT 38.270 222.760 38.550 223.040 ;
    END
  END FrameStrobe_O[8]
  PIN FrameStrobe_O[9]
    DIRECTION OUTPUT ;
    USE SIGNAL ;
    ANTENNADIFFAREA 0.702900 ;
    PORT
      LAYER met2 ;
        RECT 40.570 222.760 40.850 223.040 ;
    END
  END FrameStrobe_O[9]
  PIN N_GBUF_BEG[0]
    DIRECTION OUTPUT ;
    USE SIGNAL ;
    ANTENNADIFFAREA 0.702900 ;
    PORT
      LAYER met2 ;
        RECT 1.470 222.760 1.750 223.040 ;
    END
  END N_GBUF_BEG[0]
  PIN N_GBUF_BEG[1]
    DIRECTION OUTPUT ;
    USE SIGNAL ;
    ANTENNADIFFAREA 0.702900 ;
    PORT
      LAYER met2 ;
        RECT 3.770 222.760 4.050 223.040 ;
    END
  END N_GBUF_BEG[1]
  PIN N_GBUF_BEG[2]
    DIRECTION OUTPUT ;
    USE SIGNAL ;
    ANTENNADIFFAREA 0.702900 ;
    PORT
      LAYER met2 ;
        RECT 6.070 222.760 6.350 223.040 ;
    END
  END N_GBUF_BEG[2]
  PIN N_GBUF_BEG[3]
    DIRECTION OUTPUT ;
    USE SIGNAL ;
    ANTENNADIFFAREA 0.702900 ;
    PORT
      LAYER met2 ;
        RECT 8.370 222.760 8.650 223.040 ;
    END
  END N_GBUF_BEG[3]
  PIN N_GBUF_END[0]
    DIRECTION INPUT ;
    USE SIGNAL ;
    ANTENNAGATEAREA 0.852000 ;
    PORT
      LAYER met2 ;
        RECT 1.470 0.000 1.750 0.280 ;
    END
  END N_GBUF_END[0]
  PIN N_GBUF_END[1]
    DIRECTION INPUT ;
    USE SIGNAL ;
    ANTENNAGATEAREA 1.781100 ;
    ANTENNADIFFAREA 1.304100 ;
    PORT
      LAYER met2 ;
        RECT 3.770 0.000 4.050 0.280 ;
    END
  END N_GBUF_END[1]
  PIN N_GBUF_END[2]
    DIRECTION INPUT ;
    USE SIGNAL ;
    ANTENNAGATEAREA 1.781100 ;
    ANTENNADIFFAREA 1.304100 ;
    PORT
      LAYER met2 ;
        RECT 6.070 0.000 6.350 0.280 ;
    END
  END N_GBUF_END[2]
  PIN N_GBUF_END[3]
    DIRECTION INPUT ;
    USE SIGNAL ;
    ANTENNAGATEAREA 0.477000 ;
    PORT
      LAYER met2 ;
        RECT 8.370 0.000 8.650 0.280 ;
    END
  END N_GBUF_END[3]
  PIN RST_N_TT_PROJECT
    DIRECTION OUTPUT ;
    USE SIGNAL ;
    ANTENNADIFFAREA 0.702900 ;
    PORT
      LAYER met3 ;
        RECT 0.000 123.800 0.600 124.400 ;
    END
  END RST_N_TT_PROJECT
  PIN S_GBUF_FEED_BEG[0]
    DIRECTION OUTPUT ;
    USE SIGNAL ;
    ANTENNADIFFAREA 0.702900 ;
    PORT
      LAYER met2 ;
        RECT 10.670 0.000 10.950 0.280 ;
    END
  END S_GBUF_FEED_BEG[0]
  PIN S_GBUF_FEED_BEG[1]
    DIRECTION OUTPUT ;
    USE SIGNAL ;
    ANTENNADIFFAREA 0.702900 ;
    PORT
      LAYER met2 ;
        RECT 12.970 0.000 13.250 0.280 ;
    END
  END S_GBUF_FEED_BEG[1]
  PIN S_GBUF_FEED_BEG[2]
    DIRECTION OUTPUT ;
    USE SIGNAL ;
    ANTENNADIFFAREA 0.702900 ;
    PORT
      LAYER met2 ;
        RECT 15.270 0.000 15.550 0.280 ;
    END
  END S_GBUF_FEED_BEG[2]
  PIN S_GBUF_FEED_BEG[3]
    DIRECTION OUTPUT ;
    USE SIGNAL ;
    ANTENNADIFFAREA 0.702900 ;
    PORT
      LAYER met2 ;
        RECT 17.570 0.000 17.850 0.280 ;
    END
  END S_GBUF_FEED_BEG[3]
  PIN S_GBUF_FEED_END[0]
    DIRECTION INPUT ;
    USE SIGNAL ;
    ANTENNAGATEAREA 0.159000 ;
    PORT
      LAYER met2 ;
        RECT 10.670 222.760 10.950 223.040 ;
    END
  END S_GBUF_FEED_END[0]
  PIN S_GBUF_FEED_END[1]
    DIRECTION INPUT ;
    USE SIGNAL ;
    ANTENNAGATEAREA 0.159000 ;
    PORT
      LAYER met2 ;
        RECT 12.970 222.760 13.250 223.040 ;
    END
  END S_GBUF_FEED_END[1]
  PIN S_GBUF_FEED_END[2]
    DIRECTION INPUT ;
    USE SIGNAL ;
    ANTENNAGATEAREA 0.593700 ;
    ANTENNADIFFAREA 0.434700 ;
    PORT
      LAYER met2 ;
        RECT 15.270 222.760 15.550 223.040 ;
    END
  END S_GBUF_FEED_END[2]
  PIN S_GBUF_FEED_END[3]
    DIRECTION INPUT ;
    USE SIGNAL ;
    ANTENNAGATEAREA 0.159000 ;
    PORT
      LAYER met2 ;
        RECT 17.570 222.760 17.850 223.040 ;
    END
  END S_GBUF_FEED_END[3]
  PIN UIO_IN_TT_PROJECT0
    DIRECTION OUTPUT ;
    USE SIGNAL ;
    ANTENNADIFFAREA 0.702900 ;
    PORT
      LAYER met3 ;
        RECT 0.000 96.600 0.600 97.200 ;
    END
  END UIO_IN_TT_PROJECT0
  PIN UIO_IN_TT_PROJECT1
    DIRECTION OUTPUT ;
    USE SIGNAL ;
    ANTENNADIFFAREA 0.702900 ;
    PORT
      LAYER met3 ;
        RECT 0.000 99.320 0.600 99.920 ;
    END
  END UIO_IN_TT_PROJECT1
  PIN UIO_IN_TT_PROJECT2
    DIRECTION OUTPUT ;
    USE SIGNAL ;
    ANTENNADIFFAREA 0.702900 ;
    PORT
      LAYER met3 ;
        RECT 0.000 102.040 0.600 102.640 ;
    END
  END UIO_IN_TT_PROJECT2
  PIN UIO_IN_TT_PROJECT3
    DIRECTION OUTPUT ;
    USE SIGNAL ;
    ANTENNADIFFAREA 0.702900 ;
    PORT
      LAYER met3 ;
        RECT 0.000 104.760 0.600 105.360 ;
    END
  END UIO_IN_TT_PROJECT3
  PIN UIO_IN_TT_PROJECT4
    DIRECTION OUTPUT ;
    USE SIGNAL ;
    ANTENNADIFFAREA 0.702900 ;
    PORT
      LAYER met3 ;
        RECT 0.000 107.480 0.600 108.080 ;
    END
  END UIO_IN_TT_PROJECT4
  PIN UIO_IN_TT_PROJECT5
    DIRECTION OUTPUT ;
    USE SIGNAL ;
    ANTENNADIFFAREA 0.702900 ;
    PORT
      LAYER met3 ;
        RECT 0.000 110.200 0.600 110.800 ;
    END
  END UIO_IN_TT_PROJECT5
  PIN UIO_IN_TT_PROJECT6
    DIRECTION OUTPUT ;
    USE SIGNAL ;
    ANTENNADIFFAREA 0.702900 ;
    PORT
      LAYER met3 ;
        RECT 0.000 112.920 0.600 113.520 ;
    END
  END UIO_IN_TT_PROJECT6
  PIN UIO_IN_TT_PROJECT7
    DIRECTION OUTPUT ;
    USE SIGNAL ;
    ANTENNADIFFAREA 0.702900 ;
    PORT
      LAYER met3 ;
        RECT 0.000 115.640 0.600 116.240 ;
    END
  END UIO_IN_TT_PROJECT7
  PIN UIO_OE_TT_PROJECT0
    DIRECTION INPUT ;
    USE SIGNAL ;
    ANTENNAGATEAREA 0.477000 ;
    PORT
      LAYER met3 ;
        RECT 0.000 53.080 0.600 53.680 ;
    END
  END UIO_OE_TT_PROJECT0
  PIN UIO_OE_TT_PROJECT1
    DIRECTION INPUT ;
    USE SIGNAL ;
    ANTENNAGATEAREA 0.477000 ;
    PORT
      LAYER met3 ;
        RECT 0.000 55.800 0.600 56.400 ;
    END
  END UIO_OE_TT_PROJECT1
  PIN UIO_OE_TT_PROJECT2
    DIRECTION INPUT ;
    USE SIGNAL ;
    ANTENNAGATEAREA 0.477000 ;
    PORT
      LAYER met3 ;
        RECT 0.000 58.520 0.600 59.120 ;
    END
  END UIO_OE_TT_PROJECT2
  PIN UIO_OE_TT_PROJECT3
    DIRECTION INPUT ;
    USE SIGNAL ;
    ANTENNAGATEAREA 0.477000 ;
    PORT
      LAYER met3 ;
        RECT 0.000 61.240 0.600 61.840 ;
    END
  END UIO_OE_TT_PROJECT3
  PIN UIO_OE_TT_PROJECT4
    DIRECTION INPUT ;
    USE SIGNAL ;
    ANTENNAGATEAREA 0.477000 ;
    PORT
      LAYER met3 ;
        RECT 0.000 63.960 0.600 64.560 ;
    END
  END UIO_OE_TT_PROJECT4
  PIN UIO_OE_TT_PROJECT5
    DIRECTION INPUT ;
    USE SIGNAL ;
    ANTENNAGATEAREA 0.477000 ;
    PORT
      LAYER met3 ;
        RECT 0.000 66.680 0.600 67.280 ;
    END
  END UIO_OE_TT_PROJECT5
  PIN UIO_OE_TT_PROJECT6
    DIRECTION INPUT ;
    USE SIGNAL ;
    ANTENNAGATEAREA 0.477000 ;
    PORT
      LAYER met3 ;
        RECT 0.000 69.400 0.600 70.000 ;
    END
  END UIO_OE_TT_PROJECT6
  PIN UIO_OE_TT_PROJECT7
    DIRECTION INPUT ;
    USE SIGNAL ;
    ANTENNAGATEAREA 0.477000 ;
    PORT
      LAYER met3 ;
        RECT 0.000 72.120 0.600 72.720 ;
    END
  END UIO_OE_TT_PROJECT7
  PIN UIO_OUT_TT_PROJECT0
    DIRECTION INPUT ;
    USE SIGNAL ;
    ANTENNAGATEAREA 0.921000 ;
    PORT
      LAYER met3 ;
        RECT 0.000 31.320 0.600 31.920 ;
    END
  END UIO_OUT_TT_PROJECT0
  PIN UIO_OUT_TT_PROJECT1
    DIRECTION INPUT ;
    USE SIGNAL ;
    ANTENNAGATEAREA 0.921000 ;
    PORT
      LAYER met3 ;
        RECT 0.000 34.040 0.600 34.640 ;
    END
  END UIO_OUT_TT_PROJECT1
  PIN UIO_OUT_TT_PROJECT2
    DIRECTION INPUT ;
    USE SIGNAL ;
    ANTENNAGATEAREA 1.355700 ;
    ANTENNADIFFAREA 0.434700 ;
    PORT
      LAYER met3 ;
        RECT 0.000 36.760 0.600 37.360 ;
    END
  END UIO_OUT_TT_PROJECT2
  PIN UIO_OUT_TT_PROJECT3
    DIRECTION INPUT ;
    USE SIGNAL ;
    ANTENNAGATEAREA 0.921000 ;
    PORT
      LAYER met3 ;
        RECT 0.000 39.480 0.600 40.080 ;
    END
  END UIO_OUT_TT_PROJECT3
  PIN UIO_OUT_TT_PROJECT4
    DIRECTION INPUT ;
    USE SIGNAL ;
    ANTENNAGATEAREA 0.921000 ;
    PORT
      LAYER met3 ;
        RECT 0.000 42.200 0.600 42.800 ;
    END
  END UIO_OUT_TT_PROJECT4
  PIN UIO_OUT_TT_PROJECT5
    DIRECTION INPUT ;
    USE SIGNAL ;
    ANTENNAGATEAREA 1.355700 ;
    ANTENNADIFFAREA 0.434700 ;
    PORT
      LAYER met3 ;
        RECT 0.000 44.920 0.600 45.520 ;
    END
  END UIO_OUT_TT_PROJECT5
  PIN UIO_OUT_TT_PROJECT6
    DIRECTION INPUT ;
    USE SIGNAL ;
    ANTENNAGATEAREA 0.921000 ;
    PORT
      LAYER met3 ;
        RECT 0.000 47.640 0.600 48.240 ;
    END
  END UIO_OUT_TT_PROJECT6
  PIN UIO_OUT_TT_PROJECT7
    DIRECTION INPUT ;
    USE SIGNAL ;
    ANTENNAGATEAREA 0.921000 ;
    PORT
      LAYER met3 ;
        RECT 0.000 50.360 0.600 50.960 ;
    END
  END UIO_OUT_TT_PROJECT7
  PIN UI_IN_TT_PROJECT0
    DIRECTION OUTPUT ;
    USE SIGNAL ;
    ANTENNADIFFAREA 0.702900 ;
    PORT
      LAYER met3 ;
        RECT 0.000 74.840 0.600 75.440 ;
    END
  END UI_IN_TT_PROJECT0
  PIN UI_IN_TT_PROJECT1
    DIRECTION OUTPUT ;
    USE SIGNAL ;
    ANTENNADIFFAREA 0.702900 ;
    PORT
      LAYER met3 ;
        RECT 0.000 77.560 0.600 78.160 ;
    END
  END UI_IN_TT_PROJECT1
  PIN UI_IN_TT_PROJECT2
    DIRECTION OUTPUT ;
    USE SIGNAL ;
    ANTENNADIFFAREA 0.702900 ;
    PORT
      LAYER met3 ;
        RECT 0.000 80.280 0.600 80.880 ;
    END
  END UI_IN_TT_PROJECT2
  PIN UI_IN_TT_PROJECT3
    DIRECTION OUTPUT ;
    USE SIGNAL ;
    ANTENNADIFFAREA 0.702900 ;
    PORT
      LAYER met3 ;
        RECT 0.000 83.000 0.600 83.600 ;
    END
  END UI_IN_TT_PROJECT3
  PIN UI_IN_TT_PROJECT4
    DIRECTION OUTPUT ;
    USE SIGNAL ;
    ANTENNADIFFAREA 0.702900 ;
    PORT
      LAYER met3 ;
        RECT 0.000 85.720 0.600 86.320 ;
    END
  END UI_IN_TT_PROJECT4
  PIN UI_IN_TT_PROJECT5
    DIRECTION OUTPUT ;
    USE SIGNAL ;
    ANTENNADIFFAREA 0.702900 ;
    PORT
      LAYER met3 ;
        RECT 0.000 88.440 0.600 89.040 ;
    END
  END UI_IN_TT_PROJECT5
  PIN UI_IN_TT_PROJECT6
    DIRECTION OUTPUT ;
    USE SIGNAL ;
    ANTENNADIFFAREA 0.702900 ;
    PORT
      LAYER met3 ;
        RECT 0.000 91.160 0.600 91.760 ;
    END
  END UI_IN_TT_PROJECT6
  PIN UI_IN_TT_PROJECT7
    DIRECTION OUTPUT ;
    USE SIGNAL ;
    ANTENNADIFFAREA 0.702900 ;
    PORT
      LAYER met3 ;
        RECT 0.000 93.880 0.600 94.480 ;
    END
  END UI_IN_TT_PROJECT7
  PIN UO_OUT_TT_PROJECT0
    DIRECTION INPUT ;
    USE SIGNAL ;
    ANTENNAGATEAREA 1.514700 ;
    ANTENNADIFFAREA 0.434700 ;
    PORT
      LAYER met3 ;
        RECT 0.000 9.560 0.600 10.160 ;
    END
  END UO_OUT_TT_PROJECT0
  PIN UO_OUT_TT_PROJECT1
    DIRECTION INPUT ;
    USE SIGNAL ;
    ANTENNAGATEAREA 1.080000 ;
    PORT
      LAYER met3 ;
        RECT 0.000 12.280 0.600 12.880 ;
    END
  END UO_OUT_TT_PROJECT1
  PIN UO_OUT_TT_PROJECT2
    DIRECTION INPUT ;
    USE SIGNAL ;
    ANTENNAGATEAREA 1.080000 ;
    PORT
      LAYER met3 ;
        RECT 0.000 15.000 0.600 15.600 ;
    END
  END UO_OUT_TT_PROJECT2
  PIN UO_OUT_TT_PROJECT3
    DIRECTION INPUT ;
    USE SIGNAL ;
    ANTENNAGATEAREA 1.514700 ;
    ANTENNADIFFAREA 0.434700 ;
    PORT
      LAYER met3 ;
        RECT 0.000 17.720 0.600 18.320 ;
    END
  END UO_OUT_TT_PROJECT3
  PIN UO_OUT_TT_PROJECT4
    DIRECTION INPUT ;
    USE SIGNAL ;
    ANTENNAGATEAREA 0.921000 ;
    PORT
      LAYER met3 ;
        RECT 0.000 20.440 0.600 21.040 ;
    END
  END UO_OUT_TT_PROJECT4
  PIN UO_OUT_TT_PROJECT5
    DIRECTION INPUT ;
    USE SIGNAL ;
    ANTENNAGATEAREA 1.355700 ;
    ANTENNADIFFAREA 0.434700 ;
    PORT
      LAYER met3 ;
        RECT 0.000 23.160 0.600 23.760 ;
    END
  END UO_OUT_TT_PROJECT5
  PIN UO_OUT_TT_PROJECT6
    DIRECTION INPUT ;
    USE SIGNAL ;
    ANTENNAGATEAREA 0.921000 ;
    PORT
      LAYER met3 ;
        RECT 0.000 25.880 0.600 26.480 ;
    END
  END UO_OUT_TT_PROJECT6
  PIN UO_OUT_TT_PROJECT7
    DIRECTION INPUT ;
    USE SIGNAL ;
    ANTENNAGATEAREA 0.921000 ;
    PORT
      LAYER met3 ;
        RECT 0.000 28.600 0.600 29.200 ;
    END
  END UO_OUT_TT_PROJECT7
  PIN VGND
    DIRECTION INOUT ;
    USE GROUND ;
    PORT
      LAYER met4 ;
        RECT 12.260 0.000 13.860 223.040 ;
    END
    PORT
      LAYER met4 ;
        RECT 42.260 0.000 43.860 223.040 ;
    END
  END VGND
  PIN VPWR
    DIRECTION INOUT ;
    USE POWER ;
    PORT
      LAYER met4 ;
        RECT 6.960 0.000 8.560 223.040 ;
    END
    PORT
      LAYER met4 ;
        RECT 36.960 0.000 38.560 223.040 ;
    END
  END VPWR
  PIN W1END[0]
    DIRECTION INPUT ;
    USE SIGNAL ;
    ANTENNAGATEAREA 1.266000 ;
    PORT
      LAYER met3 ;
        RECT 64.720 24.520 65.320 25.120 ;
    END
  END W1END[0]
  PIN W1END[1]
    DIRECTION INPUT ;
    USE SIGNAL ;
    ANTENNAGATEAREA 0.981000 ;
    PORT
      LAYER met3 ;
        RECT 64.720 25.880 65.320 26.480 ;
    END
  END W1END[1]
  PIN W1END[2]
    DIRECTION INPUT ;
    USE SIGNAL ;
    ANTENNAGATEAREA 0.981000 ;
    PORT
      LAYER met3 ;
        RECT 64.720 27.240 65.320 27.840 ;
    END
  END W1END[2]
  PIN W1END[3]
    DIRECTION INPUT ;
    USE SIGNAL ;
    ANTENNAGATEAREA 1.140000 ;
    PORT
      LAYER met3 ;
        RECT 64.720 28.600 65.320 29.200 ;
    END
  END W1END[3]
  PIN W2END[0]
    DIRECTION INPUT ;
    USE SIGNAL ;
    ANTENNAGATEAREA 1.308000 ;
    PORT
      LAYER met3 ;
        RECT 64.720 40.840 65.320 41.440 ;
    END
  END W2END[0]
  PIN W2END[1]
    DIRECTION INPUT ;
    USE SIGNAL ;
    ANTENNAGATEAREA 1.308000 ;
    PORT
      LAYER met3 ;
        RECT 64.720 42.200 65.320 42.800 ;
    END
  END W2END[1]
  PIN W2END[2]
    DIRECTION INPUT ;
    USE SIGNAL ;
    ANTENNAGATEAREA 1.434000 ;
    PORT
      LAYER met3 ;
        RECT 64.720 43.560 65.320 44.160 ;
    END
  END W2END[2]
  PIN W2END[3]
    DIRECTION INPUT ;
    USE SIGNAL ;
    ANTENNAGATEAREA 1.434000 ;
    PORT
      LAYER met3 ;
        RECT 64.720 44.920 65.320 45.520 ;
    END
  END W2END[3]
  PIN W2END[4]
    DIRECTION INPUT ;
    USE SIGNAL ;
    ANTENNAGATEAREA 1.681500 ;
    PORT
      LAYER met3 ;
        RECT 64.720 46.280 65.320 46.880 ;
    END
  END W2END[4]
  PIN W2END[5]
    DIRECTION INPUT ;
    USE SIGNAL ;
    ANTENNAGATEAREA 1.681500 ;
    PORT
      LAYER met3 ;
        RECT 64.720 47.640 65.320 48.240 ;
    END
  END W2END[5]
  PIN W2END[6]
    DIRECTION INPUT ;
    USE SIGNAL ;
    ANTENNAGATEAREA 1.495200 ;
    ANTENNADIFFAREA 0.434700 ;
    PORT
      LAYER met3 ;
        RECT 64.720 49.000 65.320 49.600 ;
    END
  END W2END[6]
  PIN W2END[7]
    DIRECTION INPUT ;
    USE SIGNAL ;
    ANTENNAGATEAREA 1.060500 ;
    PORT
      LAYER met3 ;
        RECT 64.720 50.360 65.320 50.960 ;
    END
  END W2END[7]
  PIN W2MID[0]
    DIRECTION INPUT ;
    USE SIGNAL ;
    ANTENNAGATEAREA 0.252000 ;
    PORT
      LAYER met3 ;
        RECT 64.720 29.960 65.320 30.560 ;
    END
  END W2MID[0]
  PIN W2MID[1]
    DIRECTION INPUT ;
    USE SIGNAL ;
    ANTENNAGATEAREA 1.121400 ;
    ANTENNADIFFAREA 0.869400 ;
    PORT
      LAYER met3 ;
        RECT 64.720 31.320 65.320 31.920 ;
    END
  END W2MID[1]
  PIN W2MID[2]
    DIRECTION INPUT ;
    USE SIGNAL ;
    ANTENNAGATEAREA 0.537000 ;
    PORT
      LAYER met3 ;
        RECT 64.720 32.680 65.320 33.280 ;
    END
  END W2MID[2]
  PIN W2MID[3]
    DIRECTION INPUT ;
    USE SIGNAL ;
    ANTENNAGATEAREA 0.252000 ;
    PORT
      LAYER met3 ;
        RECT 64.720 34.040 65.320 34.640 ;
    END
  END W2MID[3]
  PIN W2MID[4]
    DIRECTION INPUT ;
    USE SIGNAL ;
    ANTENNAGATEAREA 0.252000 ;
    PORT
      LAYER met3 ;
        RECT 64.720 35.400 65.320 36.000 ;
    END
  END W2MID[4]
  PIN W2MID[5]
    DIRECTION INPUT ;
    USE SIGNAL ;
    ANTENNAGATEAREA 0.252000 ;
    PORT
      LAYER met3 ;
        RECT 64.720 36.760 65.320 37.360 ;
    END
  END W2MID[5]
  PIN W2MID[6]
    DIRECTION INPUT ;
    USE SIGNAL ;
    ANTENNAGATEAREA 0.906000 ;
    PORT
      LAYER met3 ;
        RECT 64.720 38.120 65.320 38.720 ;
    END
  END W2MID[6]
  PIN W2MID[7]
    DIRECTION INPUT ;
    USE SIGNAL ;
    ANTENNAGATEAREA 0.252000 ;
    PORT
      LAYER met3 ;
        RECT 64.720 39.480 65.320 40.080 ;
    END
  END W2MID[7]
  PIN W6END[0]
    DIRECTION INPUT ;
    USE SIGNAL ;
    ANTENNAGATEAREA 0.789000 ;
    PORT
      LAYER met3 ;
        RECT 64.720 73.480 65.320 74.080 ;
    END
  END W6END[0]
  PIN W6END[10]
    DIRECTION INPUT ;
    USE SIGNAL ;
    ANTENNAGATEAREA 0.560700 ;
    ANTENNADIFFAREA 0.434700 ;
    PORT
      LAYER met3 ;
        RECT 64.720 87.080 65.320 87.680 ;
    END
  END W6END[10]
  PIN W6END[11]
    DIRECTION INPUT ;
    USE SIGNAL ;
    ANTENNAGATEAREA 1.715100 ;
    ANTENNADIFFAREA 1.304100 ;
    PORT
      LAYER met3 ;
        RECT 64.720 88.440 65.320 89.040 ;
    END
  END W6END[11]
  PIN W6END[1]
    DIRECTION INPUT ;
    USE SIGNAL ;
    ANTENNAGATEAREA 0.504000 ;
    PORT
      LAYER met3 ;
        RECT 64.720 74.840 65.320 75.440 ;
    END
  END W6END[1]
  PIN W6END[2]
    DIRECTION INPUT ;
    USE SIGNAL ;
    ANTENNAGATEAREA 1.190700 ;
    ANTENNADIFFAREA 0.434700 ;
    PORT
      LAYER met3 ;
        RECT 64.720 76.200 65.320 76.800 ;
    END
  END W6END[2]
  PIN W6END[3]
    DIRECTION INPUT ;
    USE SIGNAL ;
    ANTENNAGATEAREA 0.751500 ;
    PORT
      LAYER met3 ;
        RECT 64.720 77.560 65.320 78.160 ;
    END
  END W6END[3]
  PIN W6END[4]
    DIRECTION INPUT ;
    USE SIGNAL ;
    ANTENNAGATEAREA 0.537000 ;
    PORT
      LAYER met3 ;
        RECT 64.720 78.920 65.320 79.520 ;
    END
  END W6END[4]
  PIN W6END[5]
    DIRECTION INPUT ;
    USE SIGNAL ;
    ANTENNAGATEAREA 0.252000 ;
    PORT
      LAYER met3 ;
        RECT 64.720 80.280 65.320 80.880 ;
    END
  END W6END[5]
  PIN W6END[6]
    DIRECTION INPUT ;
    USE SIGNAL ;
    ANTENNAGATEAREA 1.682100 ;
    ANTENNADIFFAREA 1.304100 ;
    PORT
      LAYER met3 ;
        RECT 64.720 81.640 65.320 82.240 ;
    END
  END W6END[6]
  PIN W6END[7]
    DIRECTION INPUT ;
    USE SIGNAL ;
    ANTENNAGATEAREA 0.378000 ;
    PORT
      LAYER met3 ;
        RECT 64.720 83.000 65.320 83.600 ;
    END
  END W6END[7]
  PIN W6END[8]
    DIRECTION INPUT ;
    USE SIGNAL ;
    ANTENNAGATEAREA 0.537000 ;
    PORT
      LAYER met3 ;
        RECT 64.720 84.360 65.320 84.960 ;
    END
  END W6END[8]
  PIN W6END[9]
    DIRECTION INPUT ;
    USE SIGNAL ;
    ANTENNAGATEAREA 0.686700 ;
    ANTENNADIFFAREA 0.434700 ;
    PORT
      LAYER met3 ;
        RECT 64.720 85.720 65.320 86.320 ;
    END
  END W6END[9]
  PIN WW4END[0]
    DIRECTION INPUT ;
    USE SIGNAL ;
    ANTENNAGATEAREA 0.789000 ;
    PORT
      LAYER met3 ;
        RECT 64.720 51.720 65.320 52.320 ;
    END
  END WW4END[0]
  PIN WW4END[10]
    DIRECTION INPUT ;
    USE SIGNAL ;
    ANTENNAGATEAREA 0.906000 ;
    PORT
      LAYER met3 ;
        RECT 64.720 65.320 65.320 65.920 ;
    END
  END WW4END[10]
  PIN WW4END[11]
    DIRECTION INPUT ;
    USE SIGNAL ;
    ANTENNAGATEAREA 0.906000 ;
    PORT
      LAYER met3 ;
        RECT 64.720 66.680 65.320 67.280 ;
    END
  END WW4END[11]
  PIN WW4END[12]
    DIRECTION INPUT ;
    USE SIGNAL ;
    ANTENNAGATEAREA 0.906000 ;
    PORT
      LAYER met3 ;
        RECT 64.720 68.040 65.320 68.640 ;
    END
  END WW4END[12]
  PIN WW4END[13]
    DIRECTION INPUT ;
    USE SIGNAL ;
    ANTENNAGATEAREA 1.340700 ;
    ANTENNADIFFAREA 0.434700 ;
    PORT
      LAYER met3 ;
        RECT 64.720 69.400 65.320 70.000 ;
    END
  END WW4END[13]
  PIN WW4END[14]
    DIRECTION INPUT ;
    USE SIGNAL ;
    ANTENNAGATEAREA 0.906000 ;
    PORT
      LAYER met3 ;
        RECT 64.720 70.760 65.320 71.360 ;
    END
  END WW4END[14]
  PIN WW4END[15]
    DIRECTION INPUT ;
    USE SIGNAL ;
    ANTENNAGATEAREA 0.906000 ;
    PORT
      LAYER met3 ;
        RECT 64.720 72.120 65.320 72.720 ;
    END
  END WW4END[15]
  PIN WW4END[1]
    DIRECTION INPUT ;
    USE SIGNAL ;
    ANTENNAGATEAREA 0.789000 ;
    PORT
      LAYER met3 ;
        RECT 64.720 53.080 65.320 53.680 ;
    END
  END WW4END[1]
  PIN WW4END[2]
    DIRECTION INPUT ;
    USE SIGNAL ;
    ANTENNAGATEAREA 0.789000 ;
    PORT
      LAYER met3 ;
        RECT 64.720 54.440 65.320 55.040 ;
    END
  END WW4END[2]
  PIN WW4END[3]
    DIRECTION INPUT ;
    USE SIGNAL ;
    ANTENNAGATEAREA 0.789000 ;
    PORT
      LAYER met3 ;
        RECT 64.720 55.800 65.320 56.400 ;
    END
  END WW4END[3]
  PIN WW4END[4]
    DIRECTION INPUT ;
    USE SIGNAL ;
    ANTENNAGATEAREA 1.097700 ;
    ANTENNADIFFAREA 0.434700 ;
    PORT
      LAYER met3 ;
        RECT 64.720 57.160 65.320 57.760 ;
    END
  END WW4END[4]
  PIN WW4END[5]
    DIRECTION INPUT ;
    USE SIGNAL ;
    ANTENNAGATEAREA 0.910500 ;
    PORT
      LAYER met3 ;
        RECT 64.720 58.520 65.320 59.120 ;
    END
  END WW4END[5]
  PIN WW4END[6]
    DIRECTION INPUT ;
    USE SIGNAL ;
    ANTENNAGATEAREA 0.663000 ;
    PORT
      LAYER met3 ;
        RECT 64.720 59.880 65.320 60.480 ;
    END
  END WW4END[6]
  PIN WW4END[7]
    DIRECTION INPUT ;
    USE SIGNAL ;
    ANTENNAGATEAREA 0.663000 ;
    PORT
      LAYER met3 ;
        RECT 64.720 61.240 65.320 61.840 ;
    END
  END WW4END[7]
  PIN WW4END[8]
    DIRECTION INPUT ;
    USE SIGNAL ;
    ANTENNAGATEAREA 0.906000 ;
    PORT
      LAYER met3 ;
        RECT 64.720 62.600 65.320 63.200 ;
    END
  END WW4END[8]
  PIN WW4END[9]
    DIRECTION INPUT ;
    USE SIGNAL ;
    ANTENNAGATEAREA 0.906000 ;
    PORT
      LAYER met3 ;
        RECT 64.720 63.960 65.320 64.560 ;
    END
  END WW4END[9]
  OBS
      LAYER nwell ;
        RECT 2.570 2.635 62.750 220.405 ;
      LAYER li1 ;
        RECT 2.760 2.635 62.560 220.405 ;
      LAYER met1 ;
        RECT 0.530 2.480 64.790 221.300 ;
      LAYER met2 ;
        RECT 0.160 222.480 1.190 222.770 ;
        RECT 2.030 222.480 3.490 222.770 ;
        RECT 4.330 222.480 5.790 222.770 ;
        RECT 6.630 222.480 8.090 222.770 ;
        RECT 8.930 222.480 10.390 222.770 ;
        RECT 11.230 222.480 12.690 222.770 ;
        RECT 13.530 222.480 14.990 222.770 ;
        RECT 15.830 222.480 17.290 222.770 ;
        RECT 18.130 222.480 19.590 222.770 ;
        RECT 20.430 222.480 21.890 222.770 ;
        RECT 22.730 222.480 24.190 222.770 ;
        RECT 25.030 222.480 26.490 222.770 ;
        RECT 27.330 222.480 28.790 222.770 ;
        RECT 29.630 222.480 31.090 222.770 ;
        RECT 31.930 222.480 33.390 222.770 ;
        RECT 34.230 222.480 35.690 222.770 ;
        RECT 36.530 222.480 37.990 222.770 ;
        RECT 38.830 222.480 40.290 222.770 ;
        RECT 41.130 222.480 42.590 222.770 ;
        RECT 43.430 222.480 44.890 222.770 ;
        RECT 45.730 222.480 47.190 222.770 ;
        RECT 48.030 222.480 49.490 222.770 ;
        RECT 50.330 222.480 51.790 222.770 ;
        RECT 52.630 222.480 54.090 222.770 ;
        RECT 54.930 222.480 56.390 222.770 ;
        RECT 57.230 222.480 58.690 222.770 ;
        RECT 59.530 222.480 60.990 222.770 ;
        RECT 61.830 222.480 63.290 222.770 ;
        RECT 64.130 222.480 65.160 222.770 ;
        RECT 0.160 0.560 65.160 222.480 ;
        RECT 0.160 0.270 1.190 0.560 ;
        RECT 2.030 0.270 3.490 0.560 ;
        RECT 4.330 0.270 5.790 0.560 ;
        RECT 6.630 0.270 8.090 0.560 ;
        RECT 8.930 0.270 10.390 0.560 ;
        RECT 11.230 0.270 12.690 0.560 ;
        RECT 13.530 0.270 14.990 0.560 ;
        RECT 15.830 0.270 17.290 0.560 ;
        RECT 18.130 0.270 19.590 0.560 ;
        RECT 20.430 0.270 21.890 0.560 ;
        RECT 22.730 0.270 24.190 0.560 ;
        RECT 25.030 0.270 26.490 0.560 ;
        RECT 27.330 0.270 28.790 0.560 ;
        RECT 29.630 0.270 31.090 0.560 ;
        RECT 31.930 0.270 33.390 0.560 ;
        RECT 34.230 0.270 35.690 0.560 ;
        RECT 36.530 0.270 37.990 0.560 ;
        RECT 38.830 0.270 40.290 0.560 ;
        RECT 41.130 0.270 42.590 0.560 ;
        RECT 43.430 0.270 44.890 0.560 ;
        RECT 45.730 0.270 47.190 0.560 ;
        RECT 48.030 0.270 49.490 0.560 ;
        RECT 50.330 0.270 51.790 0.560 ;
        RECT 52.630 0.270 54.090 0.560 ;
        RECT 54.930 0.270 56.390 0.560 ;
        RECT 57.230 0.270 58.690 0.560 ;
        RECT 59.530 0.270 60.990 0.560 ;
        RECT 61.830 0.270 63.290 0.560 ;
        RECT 64.130 0.270 65.160 0.560 ;
      LAYER met3 ;
        RECT 0.525 211.840 64.720 220.485 ;
        RECT 1.000 210.440 64.720 211.840 ;
        RECT 0.525 209.120 64.720 210.440 ;
        RECT 1.000 207.720 64.720 209.120 ;
        RECT 0.525 206.400 64.720 207.720 ;
        RECT 1.000 205.000 64.720 206.400 ;
        RECT 0.525 203.680 64.720 205.000 ;
        RECT 1.000 202.280 64.720 203.680 ;
        RECT 0.525 200.960 64.720 202.280 ;
        RECT 1.000 199.560 64.720 200.960 ;
        RECT 0.525 198.240 64.720 199.560 ;
        RECT 1.000 196.840 64.320 198.240 ;
        RECT 0.525 195.520 64.320 196.840 ;
        RECT 1.000 194.120 64.320 195.520 ;
        RECT 0.525 192.800 64.320 194.120 ;
        RECT 1.000 191.400 64.320 192.800 ;
        RECT 0.525 190.080 64.320 191.400 ;
        RECT 1.000 188.680 64.320 190.080 ;
        RECT 0.525 187.360 64.320 188.680 ;
        RECT 1.000 185.960 64.320 187.360 ;
        RECT 0.525 184.640 64.320 185.960 ;
        RECT 1.000 183.240 64.320 184.640 ;
        RECT 0.525 181.920 64.320 183.240 ;
        RECT 1.000 180.520 64.320 181.920 ;
        RECT 0.525 179.200 64.320 180.520 ;
        RECT 1.000 177.800 64.320 179.200 ;
        RECT 0.525 176.480 64.320 177.800 ;
        RECT 1.000 175.080 64.320 176.480 ;
        RECT 0.525 173.760 64.320 175.080 ;
        RECT 1.000 172.360 64.320 173.760 ;
        RECT 0.525 171.040 64.320 172.360 ;
        RECT 1.000 169.640 64.320 171.040 ;
        RECT 0.525 168.320 64.320 169.640 ;
        RECT 1.000 166.920 64.320 168.320 ;
        RECT 0.525 165.600 64.320 166.920 ;
        RECT 1.000 164.200 64.320 165.600 ;
        RECT 0.525 162.880 64.320 164.200 ;
        RECT 1.000 161.480 64.320 162.880 ;
        RECT 0.525 160.160 64.320 161.480 ;
        RECT 1.000 158.760 64.320 160.160 ;
        RECT 0.525 157.440 64.320 158.760 ;
        RECT 1.000 156.040 64.320 157.440 ;
        RECT 0.525 154.720 64.320 156.040 ;
        RECT 1.000 153.320 64.320 154.720 ;
        RECT 0.525 152.000 64.320 153.320 ;
        RECT 1.000 150.600 64.320 152.000 ;
        RECT 0.525 149.280 64.320 150.600 ;
        RECT 1.000 147.880 64.320 149.280 ;
        RECT 0.525 146.560 64.320 147.880 ;
        RECT 1.000 145.160 64.320 146.560 ;
        RECT 0.525 143.840 64.320 145.160 ;
        RECT 1.000 142.440 64.320 143.840 ;
        RECT 0.525 141.120 64.320 142.440 ;
        RECT 1.000 139.720 64.320 141.120 ;
        RECT 0.525 138.400 64.320 139.720 ;
        RECT 1.000 137.000 64.320 138.400 ;
        RECT 0.525 135.680 64.320 137.000 ;
        RECT 1.000 134.280 64.320 135.680 ;
        RECT 0.525 132.960 64.320 134.280 ;
        RECT 1.000 131.560 64.320 132.960 ;
        RECT 0.525 130.240 64.320 131.560 ;
        RECT 1.000 128.840 64.320 130.240 ;
        RECT 0.525 127.520 64.320 128.840 ;
        RECT 1.000 126.120 64.320 127.520 ;
        RECT 0.525 124.800 64.320 126.120 ;
        RECT 1.000 123.400 64.320 124.800 ;
        RECT 0.525 122.080 64.320 123.400 ;
        RECT 1.000 120.680 64.320 122.080 ;
        RECT 0.525 119.360 64.320 120.680 ;
        RECT 1.000 117.960 64.320 119.360 ;
        RECT 0.525 116.640 64.320 117.960 ;
        RECT 1.000 115.240 64.320 116.640 ;
        RECT 0.525 113.920 64.320 115.240 ;
        RECT 1.000 112.520 64.320 113.920 ;
        RECT 0.525 111.200 64.320 112.520 ;
        RECT 1.000 109.800 64.320 111.200 ;
        RECT 0.525 108.480 64.320 109.800 ;
        RECT 1.000 107.080 64.320 108.480 ;
        RECT 0.525 105.760 64.320 107.080 ;
        RECT 1.000 104.360 64.320 105.760 ;
        RECT 0.525 103.040 64.320 104.360 ;
        RECT 1.000 101.640 64.320 103.040 ;
        RECT 0.525 100.320 64.320 101.640 ;
        RECT 1.000 98.920 64.320 100.320 ;
        RECT 0.525 97.600 64.320 98.920 ;
        RECT 1.000 96.200 64.320 97.600 ;
        RECT 0.525 94.880 64.320 96.200 ;
        RECT 1.000 93.480 64.320 94.880 ;
        RECT 0.525 92.160 64.320 93.480 ;
        RECT 1.000 90.760 64.320 92.160 ;
        RECT 0.525 89.440 64.320 90.760 ;
        RECT 1.000 88.040 64.320 89.440 ;
        RECT 0.525 86.720 64.320 88.040 ;
        RECT 1.000 85.320 64.320 86.720 ;
        RECT 0.525 84.000 64.320 85.320 ;
        RECT 1.000 82.600 64.320 84.000 ;
        RECT 0.525 81.280 64.320 82.600 ;
        RECT 1.000 79.880 64.320 81.280 ;
        RECT 0.525 78.560 64.320 79.880 ;
        RECT 1.000 77.160 64.320 78.560 ;
        RECT 0.525 75.840 64.320 77.160 ;
        RECT 1.000 74.440 64.320 75.840 ;
        RECT 0.525 73.120 64.320 74.440 ;
        RECT 1.000 71.720 64.320 73.120 ;
        RECT 0.525 70.400 64.320 71.720 ;
        RECT 1.000 69.000 64.320 70.400 ;
        RECT 0.525 67.680 64.320 69.000 ;
        RECT 1.000 66.280 64.320 67.680 ;
        RECT 0.525 64.960 64.320 66.280 ;
        RECT 1.000 63.560 64.320 64.960 ;
        RECT 0.525 62.240 64.320 63.560 ;
        RECT 1.000 60.840 64.320 62.240 ;
        RECT 0.525 59.520 64.320 60.840 ;
        RECT 1.000 58.120 64.320 59.520 ;
        RECT 0.525 56.800 64.320 58.120 ;
        RECT 1.000 55.400 64.320 56.800 ;
        RECT 0.525 54.080 64.320 55.400 ;
        RECT 1.000 52.680 64.320 54.080 ;
        RECT 0.525 51.360 64.320 52.680 ;
        RECT 1.000 49.960 64.320 51.360 ;
        RECT 0.525 48.640 64.320 49.960 ;
        RECT 1.000 47.240 64.320 48.640 ;
        RECT 0.525 45.920 64.320 47.240 ;
        RECT 1.000 44.520 64.320 45.920 ;
        RECT 0.525 43.200 64.320 44.520 ;
        RECT 1.000 41.800 64.320 43.200 ;
        RECT 0.525 40.480 64.320 41.800 ;
        RECT 1.000 39.080 64.320 40.480 ;
        RECT 0.525 37.760 64.320 39.080 ;
        RECT 1.000 36.360 64.320 37.760 ;
        RECT 0.525 35.040 64.320 36.360 ;
        RECT 1.000 33.640 64.320 35.040 ;
        RECT 0.525 32.320 64.320 33.640 ;
        RECT 1.000 30.920 64.320 32.320 ;
        RECT 0.525 29.600 64.320 30.920 ;
        RECT 1.000 28.200 64.320 29.600 ;
        RECT 0.525 26.880 64.320 28.200 ;
        RECT 1.000 25.480 64.320 26.880 ;
        RECT 0.525 24.160 64.320 25.480 ;
        RECT 1.000 24.120 64.320 24.160 ;
        RECT 1.000 22.760 64.720 24.120 ;
        RECT 0.525 21.440 64.720 22.760 ;
        RECT 1.000 20.040 64.720 21.440 ;
        RECT 0.525 18.720 64.720 20.040 ;
        RECT 1.000 17.320 64.720 18.720 ;
        RECT 0.525 16.000 64.720 17.320 ;
        RECT 1.000 14.600 64.720 16.000 ;
        RECT 0.525 13.280 64.720 14.600 ;
        RECT 1.000 11.880 64.720 13.280 ;
        RECT 0.525 10.560 64.720 11.880 ;
        RECT 1.000 9.160 64.720 10.560 ;
        RECT 0.525 2.555 64.720 9.160 ;
      LAYER met4 ;
        RECT 0.310 4.255 6.560 214.705 ;
        RECT 8.960 4.255 11.860 214.705 ;
        RECT 14.260 4.255 36.560 214.705 ;
        RECT 38.960 4.255 41.860 214.705 ;
        RECT 44.260 4.255 65.010 214.705 ;
  END
END W_TT_IF
END LIBRARY

